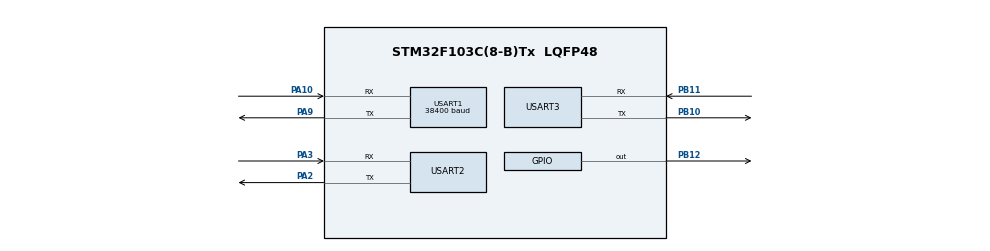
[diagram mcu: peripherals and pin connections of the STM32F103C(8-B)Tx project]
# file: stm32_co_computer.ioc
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Mcu.Family=STM32F1
NVIC.USART3_IRQn=true\:5\:0\:false\:false\:true\:true\:true\:true
FREERTOS.Tasks01=defaultTask,0,128,StartDefaultTask,Default,NULL,Dynamic,NULL,NULL
PD1-OSC_OUT.Mode=HSE-External-Oscillator
PA10.Mode=Asynchronous
PB10.Mode=Asynchronous
USART1.BaudRate=38400
PD0-OSC_IN.Signal=RCC_OSC_IN
PB11.Signal=USART3_RX
NVIC.USART2_IRQn=true\:5\:0\:false\:false\:true\:true\:true\:true
ProjectManager.StackSize=0x400
PD1-OSC_OUT.Signal=RCC_OSC_OUT
PA13.Signal=SYS_JTMS-SWDIO
PA3.Mode=Asynchronous
PA9.Mode=Asynchronous
PB11.Mode=Asynchronous
ProjectManager.TargetToolchain=STM32CubeIDE
PA9.Signal=USART1_TX
RCC.USBFreq_Value=8000000
PB10.Signal=USART3_TX
PD0-OSC_IN.Mode=HSE-External-Oscillator
board=custom
RCC.APB2Freq_Value=8000000
VP_TIM2_VS_ClockSourceINT.Mode=Internal
PA14.Mode=Serial_Wire
VP_FREERTOS_VS_CMSIS_V1.Mode=CMSIS_V1
PA13.Mode=Serial_Wire
Mcu.Name=STM32F103C(8-B)Tx
PA2.Signal=USART2_TX
Mcu.Package=LQFP48
USART2.VirtualMode=VM_ASYNC
USART3.VirtualMode=VM_ASYNC
USART1.VirtualMode=VM_ASYNC
PA10.Signal=USART1_RX
PA14.Signal=SYS_JTCK-SWCLK
ProjectManager.HeapSize=0x200
NVIC.PriorityGroup=NVIC_PRIORITYGROUP_4
PA2.Mode=Asynchronous
NVIC.USART1_IRQn=true\:5\:0\:false\:false\:true\:true\:true\:true
RCC.APB1Freq_Value=8000000
PB12.Signal=GPIO_Output
PA3.Signal=USART2_RX

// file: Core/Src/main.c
/* USER CODE BEGIN Header */
/**
 ******************************************************************************
 * @file           : main.c
 * @brief          : Main program body
 ******************************************************************************
 * @attention
 *
 * <h2><center>&copy; Copyright (c) 2021 STMicroelectronics.
 * All rights reserved.</center></h2>
 *
 * This software component is licensed by ST under BSD 3-Clause license,
 * the "License"; You may not use this file except in compliance with the
 * License. You may obtain a copy of the License at:
 *                        opensource.org/licenses/BSD-3-Clause
 *
 ******************************************************************************
 */
/* USER CODE END Header */
#include "main.h"
#include "cmsis_os.h"

/* USER CODE BEGIN Includes */
#include "stdbool.h"
#include "UART_handler.h"
#include "app_gps.h"
#include "app_pulse.h"
#include "app_deltaground.h"
/* USER CODE END Includes */

TIM_HandleTypeDef htim2;

UART_HandleTypeDef huart1;
UART_HandleTypeDef huart2;
UART_HandleTypeDef huart3;

osThreadId defaultTaskHandle;
osThreadId ledTaskHandle;
osThreadId groundTaskHandle;

void SystemClock_Config(void);
static void MX_GPIO_Init(void);
static void MX_TIM2_Init(void);
static void MX_USART1_UART_Init(void);
static void MX_USART2_UART_Init(void);
static void MX_USART3_UART_Init(void);
void queuecreate(void);

/* USER CODE BEGIN PFP */
extern uint8_t rdgps[];
//uint8_t str1[] = "$GPGGA,063841.000,4712.9592,N,03855.6132,E,1,6,1.59,40.7,M,16.4,M,,*65";
uint8_t uart_gps = 0;
uint8_t rgcs_data = 0;
uint8_t to_pc_gps_data[15] = "test message! ";
uint8_t incr_i = 0;
uint32_t period = 0;
uint32_t pulseWidth = 0;
/* USER CODE END PFP */

/* USER CODE BEGIN 0 */
QueueHandle_t xRGPSQueue = NULL;
QueueHandle_t xGRDDTQueue = NULL;
/* USER CODE END 0 */

int main(void)
{

	/* MCU Configuration--------------------------------------------------------*/

	/* Reset of all peripherals, Initializes the Flash interface and the Systick. */
	HAL_Init();

	/* USER CODE BEGIN Init */
	HAL_NVIC_SetPriority(USART1_IRQn, 15, 1);
	HAL_NVIC_SetPriority(USART3_IRQn, 15, 0);
	/* USER CODE END Init */

	/* Configure the system clock */
	SystemClock_Config();

	/* Initialize all configured peripherals */
	MX_GPIO_Init();
	MX_TIM2_Init();
	MX_USART1_UART_Init();
	MX_USART2_UART_Init();
	MX_USART3_UART_Init();
	/* USER CODE BEGIN 2 */
	HAL_TIM_IC_Start_IT(&htim2, TIM_CHANNEL_1);
	HAL_TIM_IC_Start_IT(&htim2, TIM_CHANNEL_2);
	/* USER CODE END 2 */

	/* USER CODE BEGIN RTOS_QUEUES */
	/* add queues, ... */
	queuecreate();
	/* USER CODE END RTOS_QUEUES */

	/* Create the thread(s) */
	/* definition and creation of defaultTask */
	osThreadDef(defaultTask, StartDefaultTask, osPriorityNormal, 0, 512);
	defaultTaskHandle = osThreadCreate(osThread(defaultTask), NULL);

//  osThreadDef(ledTask, StartLedTask, osPriorityLow, 0, 128);
//  ledTaskHandle = osThreadCreate(osThread(ledTask), NULL);

	osThreadDef(groundTask, StartDeltaGroundTask, osPriorityNormal, 0, 512);
	groundTaskHandle = osThreadCreate(osThread(groundTask), NULL);

	/* USER CODE BEGIN RTOS_THREADS */
	/* add threads, ... */
	HAL_UART_Receive_IT(&huart1, &uart_gps, 1);
//  HAL_UART_Transmit_IT (&huart2, str1, (sizeof(str1)/sizeof(str1[0])));
//  uint8_t *p_buff = to_pc_gps_data;
//  HAL_UART_Transmit_IT (&huart3, p_buff, strlen(to_pc_gps_data));
	HAL_UART_Receive_IT(&huart3, &rgcs_data, 1);
	/* USER CODE END RTOS_THREADS */

	/* Start scheduler */
	osKernelStart();
	/* We should never get here as control is now taken by the scheduler */
	/* Infinite loop */
	while (1)
	{

	}
}

void SystemClock_Config(void)
{
	RCC_OscInitTypeDef RCC_OscInitStruct =
	{ 0 };
	RCC_ClkInitTypeDef RCC_ClkInitStruct =
	{ 0 };

	/** Initializes the CPU, AHB and APB busses clocks
	 */
	RCC_OscInitStruct.OscillatorType = RCC_OSCILLATORTYPE_HSE;
	RCC_OscInitStruct.HSEState = RCC_HSE_ON;
	RCC_OscInitStruct.HSEPredivValue = RCC_HSE_PREDIV_DIV1;
	RCC_OscInitStruct.HSIState = RCC_HSI_ON;
	RCC_OscInitStruct.PLL.PLLState = RCC_PLL_ON;
	RCC_OscInitStruct.PLL.PLLSource = RCC_PLLSOURCE_HSE;
	RCC_OscInitStruct.PLL.PLLMUL = RCC_PLL_MUL9;
	if (HAL_RCC_OscConfig(&RCC_OscInitStruct) != HAL_OK)
	{
		Error_Handler();
	}
	/** Initializes the CPU, AHB and APB busses clocks
	 */
	RCC_ClkInitStruct.ClockType = RCC_CLOCKTYPE_HCLK | RCC_CLOCKTYPE_SYSCLK
			| RCC_CLOCKTYPE_PCLK1 | RCC_CLOCKTYPE_PCLK2;
	RCC_ClkInitStruct.SYSCLKSource = RCC_SYSCLKSOURCE_PLLCLK;
	RCC_ClkInitStruct.AHBCLKDivider = RCC_SYSCLK_DIV1;
	RCC_ClkInitStruct.APB1CLKDivider = RCC_HCLK_DIV2;
	RCC_ClkInitStruct.APB2CLKDivider = RCC_HCLK_DIV1;

	if (HAL_RCC_ClockConfig(&RCC_ClkInitStruct, FLASH_LATENCY_2) != HAL_OK)
	{
		Error_Handler();
	}
}

static void MX_TIM2_Init(void)
{

	TIM_ClockConfigTypeDef sClockSourceConfig = { 0 };
	TIM_MasterConfigTypeDef sMasterConfig =	{ 0 };
	TIM_IC_InitTypeDef sConfigIC = { 0 };

	htim2.Instance = TIM2;
	htim2.Init.Prescaler = 71;
	htim2.Init.CounterMode = TIM_COUNTERMODE_UP;
	htim2.Init.Period = 30000;
	htim2.Init.ClockDivision = TIM_CLOCKDIVISION_DIV1;
	htim2.Init.AutoReloadPreload = TIM_AUTORELOAD_PRELOAD_DISABLE;
	if (HAL_TIM_Base_Init(&htim2) != HAL_OK)
	{
		Error_Handler();
	}
	sClockSourceConfig.ClockSource = TIM_CLOCKSOURCE_INTERNAL;
	if (HAL_TIM_ConfigClockSource(&htim2, &sClockSourceConfig) != HAL_OK)
	{
		Error_Handler();
	}
	if (HAL_TIM_IC_Init(&htim2) != HAL_OK)
	{
		Error_Handler();
	}
	sMasterConfig.MasterOutputTrigger = TIM_TRGO_RESET;
	sMasterConfig.MasterSlaveMode = TIM_MASTERSLAVEMODE_DISABLE;
	if (HAL_TIMEx_MasterConfigSynchronization(&htim2, &sMasterConfig) != HAL_OK)
	{
		Error_Handler();
	}
	sConfigIC.ICPolarity = TIM_INPUTCHANNELPOLARITY_RISING;
	sConfigIC.ICSelection = TIM_ICSELECTION_DIRECTTI;
	sConfigIC.ICPrescaler = TIM_ICPSC_DIV1;
	sConfigIC.ICFilter = 0;
	if (HAL_TIM_IC_ConfigChannel(&htim2, &sConfigIC, TIM_CHANNEL_1) != HAL_OK)
	{
		Error_Handler();
	}
	sConfigIC.ICPolarity = TIM_INPUTCHANNELPOLARITY_FALLING;
	sConfigIC.ICSelection = TIM_ICSELECTION_INDIRECTTI;
	if (HAL_TIM_IC_ConfigChannel(&htim2, &sConfigIC, TIM_CHANNEL_2) != HAL_OK)
	{
		Error_Handler();
	}

}

static void MX_USART1_UART_Init(void)
{

	huart1.Instance = USART1;
	huart1.Init.BaudRate = 38400;
	huart1.Init.WordLength = UART_WORDLENGTH_8B;
	huart1.Init.StopBits = UART_STOPBITS_1;
	huart1.Init.Parity = UART_PARITY_NONE;
	huart1.Init.Mode = UART_MODE_TX_RX;
	huart1.Init.HwFlowCtl = UART_HWCONTROL_NONE;
	huart1.Init.OverSampling = UART_OVERSAMPLING_16;
	if (HAL_UART_Init(&huart1) != HAL_OK)
	{
		Error_Handler();
	}

}

static void MX_USART2_UART_Init(void)
{

	huart2.Instance = USART2;
	huart2.Init.BaudRate = 38400;
	huart2.Init.WordLength = UART_WORDLENGTH_8B;
	huart2.Init.StopBits = UART_STOPBITS_1;
	huart2.Init.Parity = UART_PARITY_NONE;
	huart2.Init.Mode = UART_MODE_TX_RX;
	huart2.Init.HwFlowCtl = UART_HWCONTROL_NONE;
	huart2.Init.OverSampling = UART_OVERSAMPLING_16;
	if (HAL_UART_Init(&huart2) != HAL_OK)
	{
		Error_Handler();
	}

}

static void MX_USART3_UART_Init(void)
{

	huart3.Instance = USART3;
	huart3.Init.BaudRate = 57600;
	huart3.Init.WordLength = UART_WORDLENGTH_8B;
	huart3.Init.StopBits = UART_STOPBITS_1;
	huart3.Init.Parity = UART_PARITY_NONE;
	huart3.Init.Mode = UART_MODE_TX_RX;
	huart3.Init.HwFlowCtl = UART_HWCONTROL_NONE;
	huart3.Init.OverSampling = UART_OVERSAMPLING_16;
	if (HAL_UART_Init(&huart3) != HAL_OK)
	{
		Error_Handler();
	}

}

static void MX_GPIO_Init(void)
{
	GPIO_InitTypeDef GPIO_InitStruct =
	{ 0 };

	/* GPIO Ports Clock Enable */
	__HAL_RCC_GPIOD_CLK_ENABLE();
	__HAL_RCC_GPIOA_CLK_ENABLE();
	__HAL_RCC_GPIOB_CLK_ENABLE();

	/*Configure GPIO pin Output Level */
	HAL_GPIO_WritePin(GPIOB, GPIO_PIN_12, GPIO_PIN_RESET);

	/*Configure GPIO pin : PB12 */
	GPIO_InitStruct.Pin = GPIO_PIN_12;
	GPIO_InitStruct.Mode = GPIO_MODE_OUTPUT_PP;
	GPIO_InitStruct.Pull = GPIO_NOPULL;
	GPIO_InitStruct.Speed = GPIO_SPEED_FREQ_LOW;
	HAL_GPIO_Init(GPIOB, &GPIO_InitStruct);

}

/* USER CODE BEGIN 4 */
void HAL_UART_RxCpltCallback(UART_HandleTypeDef *huart)
{
	BaseType_t xHigherPriorityTaskWoken = pdFALSE;
	uint8_t *p_uart_gps;

	if (huart->Instance == USART1)
	{
		p_uart_gps = start_stop(&uart_gps);
		if (p_uart_gps != 0)
		{
			if (xQueueSendFromISR(xRGPSQueue, &p_uart_gps, &xHigherPriorityTaskWoken) == errQUEUE_FULL)
			{
				asm("nop");
			}
		}
		HAL_UART_Receive_IT(&huart1, &uart_gps, 1);
	}
}
/* USER CODE BEGIN Header_StartTask02 */
/**
 * @brief Function implementing the uart_task_1 thread.
 * @param argument: Not used
 * @retval None
 */
void queuecreate(void)
{
	xRGPSQueue = xQueueCreate(30, sizeof(uint8_t*));
	xGRDDTQueue = xQueueCreate(10, sizeof(uint8_t*));

	if ((xGRDDTQueue == NULL) || (xRGPSQueue == NULL))
	{
		asm("nop");
	}
}

/* USER CODE END Header_StartTask02 */

/* USER CODE END StartTask02 */
/* USER CODE END 4 */

void HAL_TIM_IC_CaptureCallback(TIM_HandleTypeDef *htim)
{
	if (htim->Instance == TIM2)
	{
		if (htim->Channel == HAL_TIM_ACTIVE_CHANNEL_1)
		{
			period = HAL_TIM_ReadCapturedValue(&htim2, TIM_CHANNEL_1);
			pulseWidth = HAL_TIM_ReadCapturedValue(&htim2, TIM_CHANNEL_2);

			TIM2->CNT = 0;
		}
	}
}
/* USER CODE END 5 */
void Error_Handler(void)
{
	/* USER CODE BEGIN Error_Handler_Debug */
	/* User can add his own implementation to report the HAL error return state */
	__disable_irq();
	while (1)
	{
		asm("nop");
	}
	/* USER CODE END Error_Handler_Debug */
}

/************************ (C) COPYRIGHT STMicroelectronics *****END OF FILE****/

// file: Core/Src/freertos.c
/* USER CODE BEGIN Header */
/**
  ******************************************************************************
  * File Name          : freertos.c
  * Description        : Code for freertos applications
  ******************************************************************************
  * @attention
  *
  * <h2><center>&copy; Copyright (c) 2021 STMicroelectronics.
  * All rights reserved.</center></h2>
  *
  * This software component is licensed by ST under Ultimate Liberty license
  * SLA0044, the "License"; You may not use this file except in compliance with
  * the License. You may obtain a copy of the License at:
  *                             www.st.com/SLA0044
  *
  ******************************************************************************
  */
/* USER CODE END Header */

#include "FreeRTOS.h"
#include "task.h"
#include "main.h"

/* GetIdleTaskMemory prototype (linked to static allocation support) */
void vApplicationGetIdleTaskMemory( StaticTask_t **ppxIdleTaskTCBBuffer, StackType_t **ppxIdleTaskStackBuffer, uint32_t *pulIdleTaskStackSize );
/* GetTimerTaskMemory prototype (linked to static allocation support) */
void vApplicationGetTimerTaskMemory( StaticTask_t **ppxTimerTaskTCBBuffer, StackType_t **ppxTimerTaskStackBuffer, uint32_t *pulTimerTaskStackSize );

/* USER CODE BEGIN GET_IDLE_TASK_MEMORY */
static StaticTask_t xIdleTaskTCBBuffer;
static StackType_t xIdleStack[configMINIMAL_STACK_SIZE];

void vApplicationGetIdleTaskMemory( StaticTask_t **ppxIdleTaskTCBBuffer, StackType_t **ppxIdleTaskStackBuffer, uint32_t *pulIdleTaskStackSize )
{
  *ppxIdleTaskTCBBuffer = &xIdleTaskTCBBuffer;
  *ppxIdleTaskStackBuffer = &xIdleStack[0];
  *pulIdleTaskStackSize = configMINIMAL_STACK_SIZE;
  /* place for user code */
}
/* USER CODE END GET_IDLE_TASK_MEMORY */

/* USER CODE BEGIN GET_TIMER_TASK_MEMORY */
static StaticTask_t xTimerTaskTCBBuffer;
static StackType_t xTimerStack[configTIMER_TASK_STACK_DEPTH];

void vApplicationGetTimerTaskMemory( StaticTask_t **ppxTimerTaskTCBBuffer, StackType_t **ppxTimerTaskStackBuffer, uint32_t *pulTimerTaskStackSize )
{
  *ppxTimerTaskTCBBuffer = &xTimerTaskTCBBuffer;
  *ppxTimerTaskStackBuffer = &xTimerStack[0];
  *pulTimerTaskStackSize = configTIMER_TASK_STACK_DEPTH;
  /* place for user code */
}
/* USER CODE END GET_TIMER_TASK_MEMORY */

/************************ (C) COPYRIGHT STMicroelectronics *****END OF FILE****/
